VERSION 5.7 ;
  NOWIREEXTENSIONATPIN ON ;
  DIVIDERCHAR "/" ;
  BUSBITCHARS "[]" ;
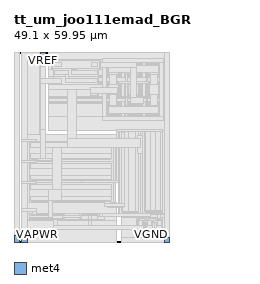
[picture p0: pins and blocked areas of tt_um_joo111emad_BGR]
MACRO tt_um_joo111emad_BGR
  CLASS BLOCK ;
  FOREIGN tt_um_joo111emad_BGR ;
  ORIGIN -8.710 -9.030 ;
  SIZE 49.100 BY 59.950 ;
  PIN VAPWR
    ANTENNAGATEAREA 395.000000 ;
    ANTENNADIFFAREA 99.435196 ;
    PORT
      LAYER met4 ;
        RECT 11.210 9.030 12.960 10.930 ;
    END
  END VAPWR
  PIN VGND
    USE GROUND ;
    PORT
      LAYER met4 ;
        RECT 56.260 9.030 57.810 10.580 ;
    END
  END VGND
  PIN VREF
    ANTENNADIFFAREA 7.250000 ;
    PORT
      LAYER met4 ;
        RECT 17.210 66.180 18.510 68.680 ;
    END
  END VREF
  PIN VDPWR
    PORT
      LAYER met4 ;
        RECT 8.710 9.030 10.460 10.930 ;
    END
  END VDPWR
  OBS
      LAYER pwell ;
        RECT 20.600 58.420 36.020 66.570 ;
        RECT 36.660 66.105 56.240 66.870 ;
        RECT 36.660 60.935 37.425 66.105 ;
        RECT 42.595 60.935 43.865 66.105 ;
        RECT 49.035 60.935 50.305 66.105 ;
        RECT 55.475 60.935 56.240 66.105 ;
        RECT 36.660 59.665 56.240 60.935 ;
        RECT 25.060 54.550 35.820 57.620 ;
        RECT 36.660 54.495 37.425 59.665 ;
        RECT 42.595 54.495 43.865 59.665 ;
        RECT 49.035 54.495 50.305 59.665 ;
        RECT 55.475 54.495 56.240 59.665 ;
        RECT 36.660 53.990 56.240 54.495 ;
        RECT 36.650 53.730 56.240 53.990 ;
        RECT 36.650 53.225 56.230 53.730 ;
        RECT 36.650 48.055 37.415 53.225 ;
        RECT 42.585 48.055 43.855 53.225 ;
        RECT 49.025 48.055 50.295 53.225 ;
        RECT 55.465 48.055 56.230 53.225 ;
        RECT 36.650 47.290 56.230 48.055 ;
      LAYER nwell ;
        RECT 12.650 20.740 40.620 41.580 ;
        RECT 12.700 15.150 25.670 18.730 ;
        RECT 28.740 14.750 36.320 18.720 ;
      LAYER pwell ;
        RECT 41.730 17.440 56.240 45.020 ;
        RECT 46.820 9.890 56.260 17.170 ;
      LAYER li1 ;
        RECT 11.210 42.880 16.810 68.980 ;
        RECT 19.710 66.570 57.810 68.980 ;
        RECT 19.710 63.500 20.600 66.570 ;
        RECT 20.780 66.220 35.840 66.390 ;
        RECT 20.780 63.850 20.950 66.220 ;
        RECT 21.430 64.330 23.590 65.740 ;
        RECT 33.030 64.330 35.190 65.740 ;
        RECT 35.670 63.850 35.840 66.220 ;
        RECT 20.780 63.680 35.840 63.850 ;
        RECT 20.780 63.500 20.950 63.680 ;
        RECT 35.670 63.500 35.840 63.680 ;
        RECT 36.020 65.580 57.810 66.570 ;
        RECT 36.020 65.565 42.415 65.580 ;
        RECT 36.020 63.500 38.010 65.565 ;
        RECT 19.710 61.310 21.160 63.500 ;
        RECT 21.430 61.790 23.590 63.200 ;
        RECT 33.030 61.790 35.190 63.200 ;
        RECT 35.460 61.475 38.010 63.500 ;
        RECT 38.275 61.785 41.745 65.255 ;
        RECT 42.055 61.475 42.415 65.565 ;
        RECT 35.460 61.310 42.415 61.475 ;
        RECT 19.710 61.140 42.415 61.310 ;
        RECT 19.710 58.880 21.160 61.140 ;
        RECT 35.460 61.115 42.415 61.140 ;
        RECT 35.460 60.795 38.010 61.115 ;
        RECT 42.735 60.795 43.725 65.580 ;
        RECT 44.045 65.565 48.855 65.580 ;
        RECT 44.045 62.030 44.405 65.565 ;
        RECT 44.010 61.475 44.410 62.030 ;
        RECT 44.715 61.785 48.185 65.255 ;
        RECT 48.495 61.475 48.855 65.565 ;
        RECT 44.010 61.115 48.855 61.475 ;
        RECT 44.010 60.795 44.410 61.115 ;
        RECT 49.175 60.795 50.165 65.580 ;
        RECT 50.485 65.565 57.810 65.580 ;
        RECT 50.485 61.930 50.845 65.565 ;
        RECT 50.460 61.475 50.845 61.930 ;
        RECT 51.155 61.785 54.625 65.255 ;
        RECT 54.860 61.475 57.810 65.565 ;
        RECT 50.460 61.115 57.810 61.475 ;
        RECT 50.460 60.795 50.810 61.115 ;
        RECT 54.860 60.795 57.810 61.115 ;
        RECT 21.430 59.250 23.590 60.660 ;
        RECT 33.030 59.250 35.190 60.660 ;
        RECT 35.460 59.805 57.810 60.795 ;
        RECT 35.460 59.485 38.010 59.805 ;
        RECT 35.460 59.480 42.415 59.485 ;
        RECT 42.735 59.480 43.725 59.805 ;
        RECT 44.010 59.485 44.410 59.805 ;
        RECT 44.010 59.480 48.855 59.485 ;
        RECT 49.175 59.480 50.165 59.805 ;
        RECT 50.460 59.485 50.810 59.805 ;
        RECT 54.860 59.485 57.810 59.805 ;
        RECT 50.460 59.480 57.810 59.485 ;
        RECT 35.460 59.125 57.810 59.480 ;
        RECT 35.460 58.880 38.010 59.125 ;
        RECT 41.560 59.080 51.260 59.125 ;
        RECT 19.710 57.030 38.010 58.880 ;
        RECT 19.710 55.080 25.660 57.030 ;
        RECT 25.890 55.380 28.050 56.790 ;
        RECT 32.830 55.380 34.990 56.790 ;
        RECT 35.460 55.080 38.010 57.030 ;
        RECT 38.275 55.345 41.745 58.815 ;
        RECT 19.710 55.035 38.010 55.080 ;
        RECT 42.055 55.035 42.415 59.080 ;
        RECT 19.710 55.030 42.415 55.035 ;
        RECT 42.735 55.030 43.725 59.080 ;
        RECT 44.010 55.035 44.410 59.080 ;
        RECT 44.715 55.345 48.185 58.815 ;
        RECT 48.495 55.035 48.855 59.080 ;
        RECT 44.010 55.030 48.855 55.035 ;
        RECT 49.175 55.030 50.165 59.080 ;
        RECT 50.460 55.035 50.845 59.080 ;
        RECT 51.155 55.345 54.625 58.815 ;
        RECT 54.860 55.035 57.810 59.125 ;
        RECT 50.460 55.030 57.810 55.035 ;
        RECT 19.710 54.675 57.810 55.030 ;
        RECT 19.710 54.355 38.010 54.675 ;
        RECT 41.560 54.630 51.160 54.675 ;
        RECT 42.735 54.355 43.725 54.630 ;
        RECT 44.010 54.355 44.410 54.630 ;
        RECT 49.175 54.355 50.165 54.630 ;
        RECT 50.460 54.355 50.810 54.630 ;
        RECT 54.860 54.355 57.810 54.675 ;
        RECT 19.710 53.365 57.810 54.355 ;
        RECT 19.710 53.045 38.010 53.365 ;
        RECT 19.710 52.685 42.405 53.045 ;
        RECT 19.710 48.595 38.010 52.685 ;
        RECT 38.265 48.905 41.735 52.375 ;
        RECT 42.045 48.595 42.405 52.685 ;
        RECT 19.710 48.480 42.405 48.595 ;
        RECT 42.725 48.480 43.715 53.365 ;
        RECT 44.010 53.045 44.410 53.365 ;
        RECT 44.010 52.685 48.845 53.045 ;
        RECT 44.010 52.130 44.410 52.685 ;
        RECT 44.035 48.595 44.395 52.130 ;
        RECT 44.705 48.905 48.175 52.375 ;
        RECT 48.485 48.595 48.845 52.685 ;
        RECT 44.035 48.480 48.845 48.595 ;
        RECT 49.165 48.480 50.155 53.365 ;
        RECT 50.460 53.045 50.810 53.365 ;
        RECT 54.860 53.045 57.810 53.365 ;
        RECT 50.460 52.685 57.810 53.045 ;
        RECT 50.460 52.330 50.835 52.685 ;
        RECT 50.475 48.595 50.835 52.330 ;
        RECT 51.145 48.905 54.615 52.375 ;
        RECT 54.860 48.595 57.810 52.685 ;
        RECT 50.475 48.480 57.810 48.595 ;
        RECT 19.710 44.330 57.810 48.480 ;
        RECT 19.710 44.280 35.460 44.330 ;
        RECT 11.210 40.880 41.110 42.880 ;
        RECT 11.210 34.560 13.460 40.880 ;
        RECT 14.115 40.350 39.155 40.520 ;
        RECT 13.730 35.290 13.900 40.290 ;
        RECT 39.370 35.290 39.540 40.290 ;
        RECT 14.115 35.060 39.155 35.230 ;
        RECT 40.060 34.560 40.230 40.880 ;
        RECT 11.210 34.390 40.230 34.560 ;
        RECT 11.210 27.930 13.460 34.390 ;
        RECT 14.115 33.720 39.155 33.890 ;
        RECT 13.730 28.660 13.900 33.660 ;
        RECT 39.370 28.660 39.540 33.660 ;
        RECT 14.115 28.430 39.155 28.600 ;
        RECT 40.060 27.930 40.230 34.390 ;
        RECT 11.210 27.760 40.230 27.930 ;
        RECT 11.210 21.430 13.460 27.760 ;
        RECT 14.115 27.090 39.155 27.260 ;
        RECT 13.730 22.030 13.900 27.030 ;
        RECT 39.370 22.030 39.540 27.030 ;
        RECT 14.115 21.800 39.155 21.970 ;
        RECT 40.060 21.430 40.230 27.760 ;
        RECT 11.210 18.170 41.160 21.430 ;
        RECT 11.210 16.230 13.460 18.170 ;
        RECT 24.760 18.160 41.160 18.170 ;
        RECT 14.165 17.500 24.205 17.670 ;
        RECT 13.780 16.440 13.950 17.440 ;
        RECT 24.420 16.440 24.590 17.440 ;
        RECT 14.165 16.230 24.205 16.380 ;
        RECT 24.760 16.230 29.460 18.160 ;
        RECT 30.030 17.470 35.030 17.640 ;
        RECT 11.210 15.830 29.460 16.230 ;
        RECT 29.800 16.215 29.970 17.255 ;
        RECT 35.090 16.215 35.260 17.255 ;
        RECT 30.030 15.830 35.030 16.000 ;
        RECT 35.560 15.830 41.160 18.160 ;
        RECT 41.970 17.850 42.140 44.330 ;
        RECT 42.870 43.920 47.870 44.090 ;
        RECT 42.640 18.710 42.810 43.750 ;
        RECT 47.930 18.710 48.100 43.750 ;
        RECT 42.870 18.370 47.870 18.540 ;
        RECT 48.600 17.980 48.770 44.330 ;
        RECT 49.200 17.980 49.370 44.330 ;
        RECT 50.100 43.920 55.100 44.090 ;
        RECT 49.870 18.710 50.040 43.750 ;
        RECT 55.160 18.710 55.330 43.750 ;
        RECT 50.100 18.370 55.100 18.540 ;
        RECT 55.610 17.980 57.810 44.330 ;
        RECT 42.560 17.850 57.810 17.980 ;
        RECT 41.970 17.680 57.810 17.850 ;
        RECT 11.210 9.030 41.160 15.830 ;
        RECT 42.560 16.630 57.810 17.680 ;
        RECT 42.560 10.480 47.460 16.630 ;
        RECT 48.090 16.090 49.130 16.260 ;
        RECT 47.750 11.030 47.920 16.030 ;
        RECT 49.300 11.030 49.470 16.030 ;
        RECT 48.090 10.800 49.130 10.970 ;
        RECT 49.990 10.480 50.160 16.630 ;
        RECT 51.020 16.090 52.060 16.260 ;
        RECT 50.680 11.030 50.850 16.030 ;
        RECT 52.230 11.030 52.400 16.030 ;
        RECT 51.020 10.800 52.060 10.970 ;
        RECT 52.920 10.480 53.090 16.630 ;
        RECT 53.950 16.090 54.990 16.260 ;
        RECT 53.610 11.030 53.780 16.030 ;
        RECT 55.160 11.030 55.330 16.030 ;
        RECT 53.950 10.800 54.990 10.970 ;
        RECT 55.610 10.480 57.810 16.630 ;
        RECT 42.560 9.030 57.810 10.480 ;
      LAYER met1 ;
        RECT 11.210 9.030 12.960 68.980 ;
        RECT 17.210 60.630 18.510 66.380 ;
        RECT 21.460 64.380 23.565 65.690 ;
        RECT 33.055 64.380 35.160 65.690 ;
        RECT 36.660 65.580 55.960 66.830 ;
        RECT 21.860 63.150 26.060 63.180 ;
        RECT 21.460 61.840 26.060 63.150 ;
        RECT 21.860 61.780 26.060 61.840 ;
        RECT 27.010 63.130 28.410 63.500 ;
        RECT 33.055 63.130 35.160 63.150 ;
        RECT 27.010 61.840 35.160 63.130 ;
        RECT 27.010 61.830 34.510 61.840 ;
        RECT 24.810 60.680 26.060 61.780 ;
        RECT 17.210 59.180 23.660 60.630 ;
        RECT 24.810 60.610 34.460 60.680 ;
        RECT 24.810 59.300 35.160 60.610 ;
        RECT 24.810 59.230 34.460 59.300 ;
        RECT 17.210 42.830 18.510 59.180 ;
        RECT 25.810 55.280 28.060 56.880 ;
        RECT 32.810 55.330 34.960 57.880 ;
        RECT 36.660 48.580 38.010 65.580 ;
        RECT 38.485 64.630 41.535 65.045 ;
        RECT 44.925 64.630 47.975 65.045 ;
        RECT 51.365 64.630 54.415 65.045 ;
        RECT 38.485 62.380 54.415 64.630 ;
        RECT 38.485 61.995 41.535 62.380 ;
        RECT 38.860 58.605 41.160 61.995 ;
        RECT 44.010 59.530 44.410 62.030 ;
        RECT 44.925 61.995 47.975 62.380 ;
        RECT 51.365 61.995 54.415 62.380 ;
        RECT 50.360 59.530 50.810 61.930 ;
        RECT 41.660 59.030 51.210 59.530 ;
        RECT 38.485 55.555 41.535 58.605 ;
        RECT 38.860 52.165 41.160 55.555 ;
        RECT 44.010 55.030 44.410 59.030 ;
        RECT 44.925 55.555 47.975 58.605 ;
        RECT 50.360 55.030 50.810 59.030 ;
        RECT 51.710 58.605 53.960 61.995 ;
        RECT 51.365 55.555 54.415 58.605 ;
        RECT 41.610 54.480 51.060 55.030 ;
        RECT 38.475 51.780 41.525 52.165 ;
        RECT 44.010 52.130 44.410 54.480 ;
        RECT 50.360 52.380 50.810 54.480 ;
        RECT 51.710 52.165 53.960 55.555 ;
        RECT 44.915 51.780 47.965 52.165 ;
        RECT 51.355 51.780 54.405 52.165 ;
        RECT 38.475 49.480 54.405 51.780 ;
        RECT 38.475 49.115 41.525 49.480 ;
        RECT 44.915 49.115 47.965 49.480 ;
        RECT 51.355 49.115 54.405 49.480 ;
        RECT 54.760 48.580 55.960 65.580 ;
        RECT 36.660 47.280 55.960 48.580 ;
        RECT 36.710 47.230 55.960 47.280 ;
        RECT 41.160 43.880 55.460 44.530 ;
        RECT 14.660 40.550 15.710 41.230 ;
        RECT 14.135 40.320 39.135 40.550 ;
        RECT 14.660 40.280 15.710 40.320 ;
        RECT 13.700 38.980 13.930 40.270 ;
        RECT 39.340 38.980 39.570 40.270 ;
        RECT 13.700 36.930 39.570 38.980 ;
        RECT 13.700 35.310 13.930 36.930 ;
        RECT 16.260 35.260 20.460 35.430 ;
        RECT 39.340 35.310 39.570 36.930 ;
        RECT 14.135 35.030 39.135 35.260 ;
        RECT 16.260 34.880 20.460 35.030 ;
        RECT 14.660 33.920 15.710 34.730 ;
        RECT 14.135 33.690 39.135 33.920 ;
        RECT 14.660 33.680 15.710 33.690 ;
        RECT 13.700 32.130 13.930 33.640 ;
        RECT 39.340 32.130 39.570 33.640 ;
        RECT 13.610 30.080 39.570 32.130 ;
        RECT 13.700 28.680 13.930 30.080 ;
        RECT 39.340 28.680 39.570 30.080 ;
        RECT 14.135 28.580 39.135 28.630 ;
        RECT 14.135 28.400 39.210 28.580 ;
        RECT 30.160 28.330 39.210 28.400 ;
        RECT 41.160 28.330 41.810 43.880 ;
        RECT 14.660 27.290 15.710 28.080 ;
        RECT 30.160 27.680 41.810 28.330 ;
        RECT 42.610 43.430 42.840 43.730 ;
        RECT 14.135 27.060 39.135 27.290 ;
        RECT 13.700 25.530 13.930 27.010 ;
        RECT 39.340 25.530 39.570 27.010 ;
        RECT 13.700 23.480 39.570 25.530 ;
        RECT 13.700 22.050 13.930 23.480 ;
        RECT 19.610 22.000 23.760 22.230 ;
        RECT 39.340 22.050 39.570 23.480 ;
        RECT 14.135 21.770 39.135 22.000 ;
        RECT 37.310 21.180 39.060 21.770 ;
        RECT 42.610 21.180 43.610 43.430 ;
        RECT 37.310 20.080 43.610 21.180 ;
        RECT 38.320 20.070 43.370 20.080 ;
        RECT 14.460 17.700 15.760 19.630 ;
        RECT 42.610 18.730 42.840 20.070 ;
        RECT 44.760 18.570 46.960 43.880 ;
        RECT 47.900 42.530 48.130 43.730 ;
        RECT 48.610 42.530 49.360 43.880 ;
        RECT 47.810 36.980 49.360 42.530 ;
        RECT 47.900 18.730 48.130 36.980 ;
        RECT 42.890 18.340 47.850 18.570 ;
        RECT 44.760 18.180 46.960 18.340 ;
        RECT 48.610 18.180 49.360 36.980 ;
        RECT 49.840 18.730 50.070 43.730 ;
        RECT 51.660 18.930 53.510 43.880 ;
        RECT 54.910 18.930 55.460 43.880 ;
        RECT 50.260 18.570 55.460 18.930 ;
        RECT 50.120 18.340 55.460 18.570 ;
        RECT 50.260 18.180 55.460 18.340 ;
        RECT 14.185 17.470 24.185 17.700 ;
        RECT 13.750 17.330 13.980 17.420 ;
        RECT 14.460 17.330 15.760 17.470 ;
        RECT 30.050 17.440 35.010 17.670 ;
        RECT 13.710 16.730 21.010 17.330 ;
        RECT 24.390 17.280 24.620 17.420 ;
        RECT 24.110 17.235 29.960 17.280 ;
        RECT 13.750 16.460 13.980 16.730 ;
        RECT 24.110 16.680 30.000 17.235 ;
        RECT 24.390 16.460 24.620 16.680 ;
        RECT 21.110 16.410 22.510 16.430 ;
        RECT 14.185 16.180 24.185 16.410 ;
        RECT 29.770 16.235 30.000 16.680 ;
        RECT 21.110 14.330 22.510 16.180 ;
        RECT 32.060 16.030 33.060 17.440 ;
        RECT 35.060 17.180 35.290 17.235 ;
        RECT 36.660 17.180 51.660 18.180 ;
        RECT 35.060 17.080 51.660 17.180 ;
        RECT 35.060 16.280 37.410 17.080 ;
        RECT 50.260 16.980 51.660 17.080 ;
        RECT 48.210 16.290 49.060 16.430 ;
        RECT 35.060 16.235 35.290 16.280 ;
        RECT 48.110 16.060 49.110 16.290 ;
        RECT 30.050 15.800 35.010 16.030 ;
        RECT 21.110 14.280 24.110 14.330 ;
        RECT 32.060 14.280 33.060 15.800 ;
        RECT 47.720 15.780 47.950 16.010 ;
        RECT 48.210 15.880 49.060 16.060 ;
        RECT 21.110 14.230 33.060 14.280 ;
        RECT 47.660 14.230 48.010 15.780 ;
        RECT 49.270 14.230 49.500 16.010 ;
        RECT 49.810 15.880 50.260 16.480 ;
        RECT 51.160 16.290 51.910 16.480 ;
        RECT 51.040 16.060 52.040 16.290 ;
        RECT 50.650 15.880 50.880 16.010 ;
        RECT 51.160 15.880 51.910 16.060 ;
        RECT 49.810 15.130 50.910 15.880 ;
        RECT 21.110 12.830 49.500 14.230 ;
        RECT 47.660 11.280 48.010 12.830 ;
        RECT 47.660 10.780 49.110 11.280 ;
        RECT 49.270 11.050 49.500 12.830 ;
        RECT 50.610 14.230 50.910 15.130 ;
        RECT 52.200 14.230 52.430 16.010 ;
        RECT 52.760 15.880 53.210 16.480 ;
        RECT 54.060 16.290 54.810 17.580 ;
        RECT 53.970 16.060 54.970 16.290 ;
        RECT 53.580 15.880 53.810 16.010 ;
        RECT 54.060 15.880 54.810 16.060 ;
        RECT 52.760 15.130 53.860 15.880 ;
        RECT 50.610 12.830 52.430 14.230 ;
        RECT 50.610 11.280 50.910 12.830 ;
        RECT 50.610 11.000 51.960 11.280 ;
        RECT 52.200 11.050 52.430 12.830 ;
        RECT 53.560 14.230 53.860 15.130 ;
        RECT 55.130 14.230 55.360 16.010 ;
        RECT 53.560 12.830 55.360 14.230 ;
        RECT 53.560 11.280 53.860 12.830 ;
        RECT 53.560 11.000 54.910 11.280 ;
        RECT 55.130 11.050 55.360 12.830 ;
        RECT 50.610 10.780 52.040 11.000 ;
        RECT 53.560 10.780 54.970 11.000 ;
        RECT 48.110 10.770 49.110 10.780 ;
        RECT 51.040 10.770 52.040 10.780 ;
        RECT 53.970 10.770 54.970 10.780 ;
        RECT 56.560 10.330 57.510 68.630 ;
      LAYER met2 ;
        RECT 11.660 10.930 12.510 67.080 ;
        RECT 17.260 64.680 18.360 66.180 ;
        RECT 36.020 64.230 47.510 65.730 ;
        RECT 14.660 40.680 15.660 41.180 ;
        RECT 17.210 35.430 18.510 44.630 ;
        RECT 25.685 41.580 28.435 57.105 ;
        RECT 32.810 56.030 41.410 57.880 ;
        RECT 32.810 55.330 34.960 56.030 ;
        RECT 45.460 54.580 47.510 64.230 ;
        RECT 45.460 52.580 49.510 54.580 ;
        RECT 16.260 34.880 20.460 35.430 ;
        RECT 14.660 34.130 15.660 34.630 ;
        RECT 14.660 27.480 15.660 27.980 ;
        RECT 20.810 25.530 23.760 38.980 ;
        RECT 25.685 38.830 48.610 41.580 ;
        RECT 19.610 22.030 23.760 25.530 ;
        RECT 14.460 18.680 15.710 19.530 ;
        RECT 19.610 16.880 21.010 22.030 ;
        RECT 48.210 15.880 50.260 16.480 ;
        RECT 51.160 15.880 53.210 16.480 ;
        RECT 56.810 10.580 57.410 68.230 ;
      LAYER met3 ;
        RECT 11.210 9.030 12.960 68.980 ;
        RECT 17.285 64.630 18.335 66.230 ;
        RECT 14.685 40.630 15.635 41.230 ;
        RECT 14.685 34.080 15.635 34.680 ;
        RECT 14.685 27.430 15.635 28.030 ;
        RECT 14.485 18.630 15.685 19.580 ;
        RECT 56.835 10.530 57.385 68.280 ;
      LAYER met4 ;
        RECT 8.710 10.930 10.460 68.980 ;
        RECT 11.210 41.230 12.960 68.980 ;
        RECT 17.210 64.530 18.510 66.180 ;
        RECT 11.210 40.630 15.710 41.230 ;
        RECT 11.210 34.730 12.960 40.630 ;
        RECT 11.210 34.030 15.710 34.730 ;
        RECT 11.210 28.080 12.960 34.030 ;
        RECT 11.210 27.380 15.710 28.080 ;
        RECT 11.210 19.630 12.960 27.380 ;
        RECT 11.210 18.530 15.760 19.630 ;
        RECT 11.210 10.930 12.960 18.530 ;
        RECT 56.260 10.580 57.810 68.980 ;
  END
END tt_um_joo111emad_BGR
END LIBRARY

